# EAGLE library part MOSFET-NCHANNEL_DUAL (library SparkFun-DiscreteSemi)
Dual N-Channel 30-V (D-S) MOSFET FDMA1024NZ TRANS-09516 http://www.vishay.com/docs/71053/71053.pdf

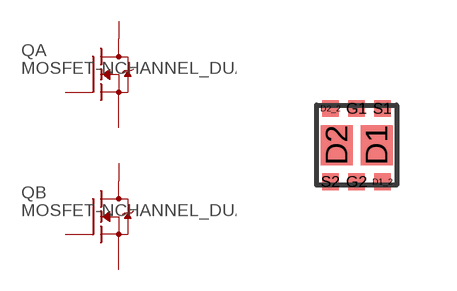
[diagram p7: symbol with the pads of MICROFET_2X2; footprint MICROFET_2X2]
Designator prefix Q; gates A=N-MOSFET-G2DS-D B=N-MOSFET-G2DS-D

## MOSFET-NCHANNEL_DUALFDMA1024NZ (PROD_ID: TRANS-09516)  [MICROFET_2X2]
D1  A:D  pas
D1_2  A:D1  pas
D2  B:D  pas
D2_2  B:D1  pas
G1  A:G  pas
G2  B:G  pas
S1  A:S  pas
S2  B:S  pas

## Footprint MICROFET_2X2 (pad centres in mm)
1206-8 ChipFET Source: http://www.vishay.com/docs/72593/72593.pdf http://www.vishay.com/docs/71151/71151.pdf
smd 0.8 x 1: D1 0.5,0; D2 -0.5,0
smd 0.42 x 0.42: D1_2 0.65,-0.915; D2_2 -0.65,0.915; G1 0,0.915; G2 0,-0.915; S1 0.65,0.915; S2 -0.65,-0.915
